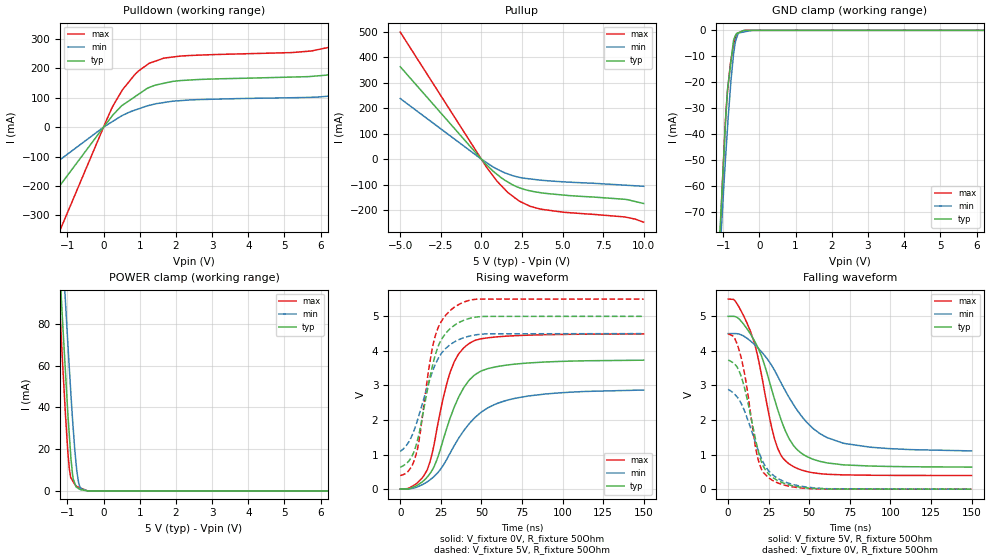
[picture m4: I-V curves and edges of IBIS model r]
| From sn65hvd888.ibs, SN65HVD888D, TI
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|   r Model
[Model]   r
Model_type   3-state
Polarity   Non-Inverting
Vmeas = 2.5
Vref = 2.5
Cref = 2pF
Rref = 50
|   typ   min   max
|   (nom PVT)   (fast PVT)   (slow PVT)
|C_comp from frequency sweep method (F=125KHz)
|C_comp   1.495e-10   1.150e-10   1.824e-10
|ON state : BUFFER OUTPUT TURNED HIGH
|C_comp   1.495e-10   1.150e-10   1.824e-10
|OFF state: BUFFER IN HIGH IMPEDANCE
|C_comp   4.798e-12   4.384e-12   5.241e-12
|C_comp from LC tank measurement(L=1nH)
|Resonant Frequency(Hz)   2.830e+09   3.020e+09   2.690e+09
 C_comp   3.166e-12   2.780e-12   3.504e-12
|ON state : BUFFER OUTPUT TURNED HIGH
|Resonant Frequency(Hz)   2.830e+09   3.020e+09   2.690e+09
|C_comp   3.166e-12   2.780e-12   3.504e-12
|OFF state: BUFFER IN HIGH IMPEDANCE
|Resonant Frequency(Hz)   2.980e+09   3.140e+09   2.880e+09
|C_comp   2.855e-12   2.572e-12   3.057e-12
| Where nom  PVT is Nominal Process, 5V, 27C
|   Fast PVT is Strong Process,  5.5V, -40C
|   Slow PVT is Weak Process,   4.5V, 125C
[Voltage Range]   5   4.5   5.5
|Ambient Temperature   25   85   -40
|Junction Temperature
[Temperature Range]   27   125   -40
[Pullup Reference]   5   4.5   5.5
[Pulldown Reference]   0   0   0
[Power Clamp Reference]   5   4.5   5.5
[GND Clamp Reference]   0   0   0
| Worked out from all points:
|   slope of the pulldown table from 0 to 0.75 V, typ, clamps not added: 8.01 ohm
|   slope of the pullup table from 0 to 0.75 V, typ, clamps not added: 15.5 ohm
|   GND clamp passes 1 mA (typ) near -0.59 V on its own axis
|   POWER clamp passes 1 mA (typ) near -0.68 V on its own axis
|   falling waveform, V_fixture 5V, R_fixture 50Ohm: 20-80 % time 19ns typ, 28.4ns min, 14.5ns max; typ from 5 V to 0.638 V
|   rising waveform, V_fixture 0V, R_fixture 50Ohm: 20-80 % time 18.2ns typ, 27.3ns min, 13.6ns max; typ from 0 V to 3.73 V
|   rising waveform, V_fixture 5V, R_fixture 50Ohm: 20-80 % time 12.2ns typ, 14.8ns min, 10.3ns max; typ from 0.635 V to 5 V
|   falling waveform, V_fixture 0V, R_fixture 50Ohm: 20-80 % time 11.1ns typ, 14.5ns min, 9.3ns max; typ from 3.74 V to 0 V
[Pulldown]
|   Voltage   I(typ)   I(min)   I(max)
-5V       -822.3mA   -460.4mA   -1.456A
-4.5mV    -740.1uA   -414.4uA   -1.31mA
522.5mV   74.52mA    39.88mA    127.1mA
874.5mV   104mA      58.16mA    180.1mA
1.265V    135mA      74.09mA    217.1mA
2.118V    158.1mA    90mA       241.4mA
5.737V    172.3mA    101.3mA    258.6mA
6.885V    195.8mA    112.5mA    302.7mA
7.81V     256.8mA    149.4mA    409mA
8.602V    370.2mA    204.2mA    600.7mA
9.664V    672.7mA    329.7mA    1.08A
10V       798.2mA    369.6mA    1.3A
[GND Clamp]
|   Voltage   I(typ)   I(min)   I(max)
-5V       -1.663A    -1.421A    -1.927A
-1.085V   -75.85mA   -84.47mA   -79.21mA
-1.023V   -58.9mA    -69.61mA   -58.82mA
-935mV    -34.66mA   -48.94mA   -34.05mA
-880mV    -22.6mA    -37.16mA   -23.23mA
-803mV    -13.86mA   -22.52mA   -13.14mA
-783mV    -11.59mA   -18.85mA   -11.3mA
-715mV    -3.873mA   -9.28mA    -5.401mA
-652.5mV  -1.723mA   -3.775mA   -2.647mA
-580.5mV  -943.3uA   -1.033mA   -964.3uA
-435mV    -25.86uA   -635.9uA   -185.2uA
10V       0A         0A         0A
[Pullup]
|   Voltage   I(typ)   I(min)   I(max)
-5V       363.7mA    238.5mA    499.8mA
335.5mV   -23.11mA   -14.22mA   -33.28mA
968mV     -59.94mA   -38.98mA   -86.91mA
1.672V    -91.39mA   -58.89mA   -133.2mA
2.376V    -113.3mA   -72mA      -166.2mA
2.959V    -124mA     -77.39mA   -184mA
3.547V    -130.8mA   -81.81mA   -194.7mA
5.027V    -140.9mA   -88.99mA   -208.3mA
8.85V     -157.9mA   -102.2mA   -227.2mA
9.471V    -166.3mA   -104.6mA   -235.6mA
10V       -174.4mA   -106.7mA   -247.8mA
[POWER Clamp]
|   Voltage   I(typ)   I(min)   I(max)
-5V       1.49A      1.478A     1.515A
-1.373V   160.4mA    192.8mA    143mA
-1.14V    83.35mA    118.2mA    63.82mA
-1.062V   59.6mA     93.17mA    39.33mA
-990mV    37.68mA    71.37mA    19.36mA
-946mV    26.56mA    58.56mA    10.54mA
-900mV    15.16mA    45.59mA    6.169mA
-855mV    7.547mA    33.68mA    4.864mA
-738mV    1.705mA    9.296mA    2.12mA
-688.5mV  1.1mA      3.894mA    1.763mA
-630mV    566.9uA    1.246mA    1.341mA
10V       0A         0A         0A
[Ramp]
R_load = 50
|   typ   min   max
dV/dt_r   2.23907/1.80688e-08   1.7209/2.71764e-08   2.69435/1.34681e-08
dV/dt_f   2.61695/1.90148e-08   2.03585/2.84067e-08   3.06325/1.44155e-08
[Falling Waveform]
V_fixture = 5V
V_fixture_min = 4.5V
V_fixture_max = 5.5V
R_fixture = 50Ohm
|   Time   V(typ)   V(min)   V(max)
0s        5V         4.5V       5.5V
4.56ns    4.989V     4.5V       5.429V
13.86ns   4.482V     4.283V     4.551V
20.55ns   3.85V      3.973V     3.306V
28.74ns   2.576V     3.424V     1.429V
32.52ns   2.019V     3.085V     984.1mV
37.14ns   1.499V     2.687V     745.1mV
52.47ns   862.7mV    1.751V     473.6mV
70.39ns   706.5mV    1.337V     414.4mV
150ns     638.4mV    1.107V     394.6mV
[Rising Waveform]
V_fixture = 0V
V_fixture_min = 0V
V_fixture_max = 0V
R_fixture = 50Ohm
|   Time   V(typ)   V(min)   V(max)
0s        905.4pV    46.66nV    283.7pV
9.35ns    83.25mV    44.73mV    137.6mV
16.65ns   350.7mV    212.8mV    563.1mV
22.55ns   845.1mV    448.3mV    1.729V
30.73ns   2.056V     1.043V     3.38V
35.93ns   2.658V     1.469V     3.908V
42.7ns    3.165V     1.905V     4.224V
54.29ns   3.491V     2.361V     4.381V
71.75ns   3.623V     2.638V     4.443V
150ns     3.732V     2.868V     4.491V
[Rising Waveform]
V_fixture = 5V
V_fixture_min = 4.5V
V_fixture_max = 5.5V
R_fixture = 50Ohm
|   Time   V(typ)   V(min)   V(max)
0s        635.2mV    1.09V      394mV
6.21ns    875.2mV    1.446V     599.6mV
10.5ns    1.391V     1.977V     1.137V
12.37ns   1.772V     2.274V     1.65V
18.11ns   3.192V     3.16V      3.626V
21.9ns    3.928V     3.64V      4.484V
25.3ns    4.326V     3.926V     4.853V
33.14ns   4.734V     4.254V     5.257V
51.2ns    4.996V     4.488V     5.5V
150ns     5V         4.5V       5.5V
[Falling Waveform]
V_fixture = 0V
V_fixture_min = 0V
V_fixture_max = 0V
R_fixture = 50Ohm
|   Time   V(typ)   V(min)   V(max)
0s        3.739V     2.891V     4.493V
4.09ns    3.615V     2.74V      4.357V
8.12ns    3.25V      2.472V     3.784V
11.38ns   2.675V     2.098V     2.991V
16.66ns   1.487V     1.376V     1.258V
18.98ns   1.03V      1.071V     775.8mV
22.5ns    591.3mV    698.9mV    442.1mV
26.93ns   357.5mV    436.4mV    264.6mV
56.57ns   11.43mV    25mV       3.969mV
150ns     2.628uV    7.767uV    820.3nV
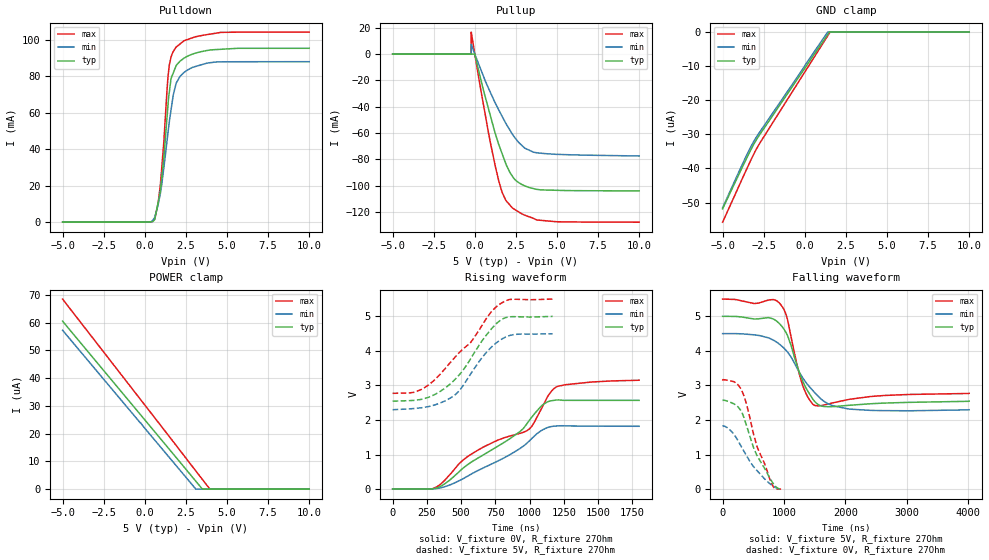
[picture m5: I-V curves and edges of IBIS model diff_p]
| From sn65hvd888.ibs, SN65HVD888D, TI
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|   diff Model
[Model]   diff_p
Model_type   I/O
Polarity   Non-Inverting
Enable   Active-High
Vinl = 0.8
Vinh = 2
Vmeas = 2.5
Vref = 2.5
Cref = 50pF
Rref = 27
|   typ   min   max
|   (nom PVT)   (fast PVT)   (slow PVT)
|C_comp from frequency sweep method (F=125KHz)
|Average
|C_comp   9.846e-10   2.587e-10   1.376e-09
|ON state : BUFFER OUTPUT TURNED HIGH
|C_comp   1.960e-09   5.074e-10   2.742e-09
|OFF state: BUFFER IN HIGH IMPEDANCE
C_comp   9.656e-12   9.606e-12   9.919e-12
|C_comp from LC tank measurement(L=1nH )
|Average
|Resonant Frequency(Hz)   2.210e+09   2.275e+09   2.12e+09
| C_comp   5.230e-12   4.977e-12   5.687e-12
|ON state : BUFFER OUTPUT TURNED HIGH
|Resonant Frequency(Hz)   2.100e+09   2.110e+09   2.010e+09
| C_comp   5.750e-12   5.695e-12   6.276e-12
|OFF state: BUFFER IN HIGH IMPEDANCE
|Resonant Frequency(Hz)   2.320e+09   2.440e+09   2.230e+09
|C_comp   4.711e-12   4.259e-12   5.099e-12
| Where nom  PVT is Nominal Process, 5V, 27C
|   Fast PVT is Strong Process,  5.5V, -40C
|   Slow PVT is Weak Process,   4.5V, 125C
[Voltage Range]   5   4.5   5.5
|Ambient Temperature   25   85   -40
|Junction Temperature
[Temperature Range]   27   125   -40
[Pullup Reference]   5   4.5   5.5
[Pulldown Reference]   0   0   0
[Power Clamp Reference]   5   4.5   5.5
[GND Clamp Reference]   0   0   0
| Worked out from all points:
|   slope of the pulldown table from 0 to 0.75 V, typ, clamps not added: 92.7 ohm
|   slope of the pullup table from 0 to 0.75 V, typ, clamps not added: 19.9 ohm
|   falling waveform, V_fixture 5V, R_fixture 27Ohm: 20-80 % time 289ns typ, 519ns min, 201ns max; typ from 5 V to 2.55 V
|   rising waveform, V_fixture 0V, R_fixture 27Ohm: 20-80 % time 522ns typ, 471ns min, 648ns max; typ from 0 V to 2.57 V
|   rising waveform, V_fixture 5V, R_fixture 27Ohm: 20-80 % time 276ns typ, 249ns min, 342ns max; typ from 2.55 V to 5 V
|   falling waveform, V_fixture 0V, R_fixture 27Ohm: 20-80 % time 360ns typ, 415ns min, 328ns max; typ from 2.57 V to 0 V
[Pulldown]
|   Voltage   I(typ)   I(min)   I(max)
-5V       0A         0A         0A
599.5mV   1.483mA    2.701mA    1.704mA
808.5mV   10.72mA    9.647mA    10.26mA
940.5mV   16.87mA    15.44mA    20.12mA
1.155V    34.87mA    29.62mA    43.62mA
1.342V    56.38mA    43.81mA    71.14mA
1.49V     71.3mA     55.01mA    86.23mA
1.595V    78.84mA    61.54mA    90.63mA
1.908V    85.97mA    76.32mA    96.15mA
2.376V    89.99mA    82.14mA    99.54mA
4.253V    94.72mA    87.87mA    103.6mA
10V       95.48mA    88.11mA    104.4mA
[GND Clamp]
|   Voltage   I(typ)   I(min)   I(max)
-5V       -51.86uA   -51.56uA   -55.78uA
-3.618V   -37.81uA   -36.94uA   -41.05uA
-3.348V   -35.16uA   -34.26uA   -38.25uA
-2.979V   -31.87uA   -31.07uA   -34.6uA
1.391V    -727.2nA   -11.06nA   -1.113uA
1.49V     -20.19nA   0A         -354.6nA
1.534V    -18.05nA   0A         -15.41nA
10V       0A         0A         0A
[Pullup]
|   Voltage   I(typ)   I(min)   I(max)
-5V       0A         0A         0A
-220.5mV  0A         0A         0A
-216mV    8.022nA    7.47mA     16.79mA
0V        0A         0A         0A
830.5mV   -41.37mA   -25.83mA   -59.55mA
1.27V     -61.27mA   -37.72mA   -86.48mA
1.672V    -75.95mA   -47.52mA   -105.3mA
2.272V    -92.48mA   -60.52mA   -116.6mA
3.038V    -100.1mA   -71.38mA   -122.4mA
3.568V    -102.2mA   -74.52mA   -124.8mA
4.944V    -103.5mA   -76.15mA   -127.4mA
10V       -103.9mA   -77.39mA   -127.7mA
[POWER Clamp]
|   Voltage   I(typ)   I(min)   I(max)
-5V       60.53uA    57.22uA    68.48uA
3.105V    2.86uA     20.72nA    6.55uA
3.505V    15.34nA    0A         3.496uA
3.96V     0A         0A         26.51nA
10V       0A         0A         0A
[Ramp]
R_load = 27
|   typ   min   max
dV/dt_r   1.54172/5.22245e-07   1.08966/4.7065e-07   1.89926/6.48578e-07
dV/dt_f   1.47458/2.87919e-07   1.32296/5.19379e-07   1.63872/2.01531e-07
[Falling Waveform]
V_fixture = 5V
V_fixture_min = 4.5V
V_fixture_max = 5.5V
R_fixture = 27Ohm
|   Time   V(typ)   V(min)   V(max)
0s        5V         4.5V       5.5V
608.6ns   4.934V     4.441V     5.397V
821.1ns   4.928V     4.317V     5.485V
938.3ns   4.765V     4.176V     5.358V
1.05us    4.467V     3.981V     4.95V
1.3us     3.142V     3.232V     3.018V
1.503us   2.529V     2.785V     2.421V
1.713us   2.386V     2.474V     2.462V
2.074us   2.428V     2.316V     2.603V
4.013us   2.546V     2.298V     2.772V
[Rising Waveform]
V_fixture = 0V
V_fixture_min = 0V
V_fixture_max = 0V
R_fixture = 27Ohm
|   Time   V(typ)   V(min)   V(max)
0s        285.9uV    266.1uV    315.9uV
323.8ns   36.16mV    20.04mV    71.21mV
586.7ns   815.1mV    465.2mV    1.043V
926.5ns   1.657V     1.169V     1.611V
996.8ns   1.986V     1.393V     1.738V
1.091us   2.427V     1.709V     2.366V
1.141us   2.541V     1.796V     2.739V
1.196us   2.579V     1.828V     2.96V
1.269us   2.571V     1.829V     3.026V
1.799us   2.57V      1.819V     3.152V
[Rising Waveform]
V_fixture = 5V
V_fixture_min = 4.5V
V_fixture_max = 5.5V
R_fixture = 27Ohm
|   Time   V(typ)   V(min)   V(max)
0s        2.546V     2.298V     2.772V
155.9ns   2.569V     2.333V     2.801V
214.9ns   2.601V     2.357V     2.893V
389ns     2.943V     2.566V     3.516V
480.8ns   3.282V     2.825V     3.93V
569.4ns   3.773V     3.334V     4.246V
673.2ns   4.403V     3.906V     4.871V
789.5ns   4.894V     4.324V     5.373V
888.7ns   4.99V      4.475V     5.494V
1.168us   4.998V     4.496V     5.499V
[Falling Waveform]
V_fixture = 0V
V_fixture_min = 0V
V_fixture_max = 0V
R_fixture = 27Ohm
|   Time   V(typ)   V(min)   V(max)
0s        2.57V      1.816V     3.166V
128ns     2.513V     1.7V       3.135V
288.7ns   2.295V     1.281V     2.929V
392ns     1.827V     959.4mV    2.439V
521.9ns   1.123V     613.6mV    1.474V
560.8ns   972.1mV    536mV      1.228V
691.4ns   577mV      283.5mV    701.7mV
791.6ns   251.1mV    126.2mV    188.4mV
861.5ns   80.11mV    48.63mV    10.42mV
951.7ns   453.4uV    850.7uV    570.3uV
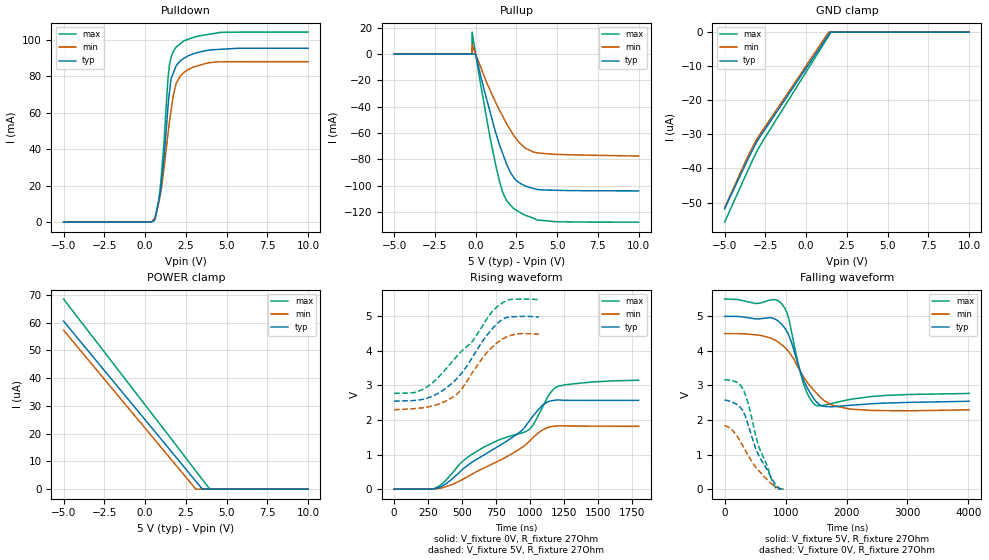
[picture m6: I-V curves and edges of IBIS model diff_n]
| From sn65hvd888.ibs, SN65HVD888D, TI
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[Model]   diff_n
Model_type   I/O
Polarity   Non-Inverting
Enable   Active-High
Vinl = 0.8
Vinh = 2
Vmeas = 2.5
Vref = 2.5
Cref = 50pF
Rref = 27
|   typ   min   max
|   (nom PVT)   (fast PVT)   (slow PVT)
|C_comp from frequency sweep method (F=125KHz)
|Average
| C_comp   4.287e-09   3.218e-09   4.932e-09
|ON state : BUFFER OUTPUT TURNED HIGH
| C_comp   8.564e-09   6.426e-09   9.855e-09
|OFF state: BUFFER IN HIGH IMPEDANCE
C_comp   9.656e-12  9.606e-12   9.919e-12
|C_comp from LC tank measurement(L=1nH )
|Average
|Resonant Frequency(Hz)   1.865e+09   1.975e+09   1.77e+09
| C_comp   8.7305e-12   7.6895e-12   9.9395e-12
|ON state : BUFFER OUTPUT TURNED HIGH
|Resonant Frequency(Hz)   1.410e+09   1.510e+09   1.310e+09
| C_comp   1.275e-11   1.112e-11   1.478e-11
|OFF state: BUFFER IN HIGH IMPEDANCE
|Resonant Frequency(Hz)   2.320e+09   2.440e+09   2.230e+09
|C_comp   4.711e-12   4.259e-12   5.099e-12
| Where nom  PVT is Nominal Process, 5V, 27C
|   Fast PVT is Strong Process,  5.5V, -40C
|   Slow PVT is Weak Process,   4.5V, 125C
[Voltage Range]   5   4.5   5.5
|Ambient Temperature   25   85   -40
|Junction Temperature
[Temperature Range]   27   125   -40
[Pullup Reference]   5   4.5   5.5
[Pulldown Reference]   0   0   0
[Power Clamp Reference]   5   4.5   5.5
[GND Clamp Reference]   0   0   0
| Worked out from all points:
|   slope of the pulldown table from 0 to 0.75 V, typ, clamps not added: 92.7 ohm
|   slope of the pullup table from 0 to 0.75 V, typ, clamps not added: 19.9 ohm
|   falling waveform, V_fixture 5V, R_fixture 27Ohm: 20-80 % time 289ns typ, 519ns min, 201ns max; typ from 5 V to 2.55 V
|   rising waveform, V_fixture 0V, R_fixture 27Ohm: 20-80 % time 522ns typ, 471ns min, 648ns max; typ from 0 V to 2.57 V
|   rising waveform, V_fixture 5V, R_fixture 27Ohm: 20-80 % time 274ns typ, 247ns min, 340ns max; typ from 2.55 V to 4.98 V
|   falling waveform, V_fixture 0V, R_fixture 27Ohm: 20-80 % time 360ns typ, 415ns min, 328ns max; typ from 2.57 V to 0 V
[Pulldown]
|   Voltage   I(typ)   I(min)   I(max)
-5V       0A         0A         0A
599.5mV   1.483mA    2.701mA    1.704mA
808.5mV   10.72mA    9.647mA    10.26mA
940.5mV   16.87mA    15.44mA    20.12mA
1.155V    34.87mA    29.62mA    43.62mA
1.342V    56.38mA    43.81mA    71.14mA
1.49V     71.3mA     55.01mA    86.23mA
1.595V    78.84mA    61.54mA    90.63mA
1.908V    85.97mA    76.32mA    96.15mA
2.376V    89.99mA    82.14mA    99.54mA
4.253V    94.72mA    87.87mA    103.6mA
10V       95.48mA    88.11mA    104.4mA
[GND Clamp]
|   Voltage   I(typ)   I(min)   I(max)
-5V       -51.83uA   -51.53uA   -55.75uA
-3.623V   -37.83uA   -36.96uA   -41.07uA
-3.127V   -33.1uA    -32.24uA   -36uA
-2.75V    -30.12uA   -29.37uA   -32.66uA
1.386V    -732.6nA   -18.89nA   -1.118uA
1.485V    -29.22nA   0A         -363nA
1.529V    0A         0A         -27.59nA
10V       0A         0A         0A
[Pullup]
|   Voltage   I(typ)   I(min)   I(max)
-5V       0A         0A         0A
-220.5mV  0A         0A         0A
-216mV    8.022nA    7.47mA     16.79mA
0V        0A         0A         0A
830.5mV   -41.37mA   -25.83mA   -59.55mA
1.27V     -61.27mA   -37.72mA   -86.48mA
1.672V    -75.95mA   -47.52mA   -105.3mA
2.272V    -92.48mA   -60.52mA   -116.6mA
3.038V    -100.1mA   -71.38mA   -122.4mA
3.568V    -102.2mA   -74.52mA   -124.8mA
4.944V    -103.5mA   -76.15mA   -127.4mA
10V       -103.9mA   -77.39mA   -127.7mA
[POWER Clamp]
|   Voltage   I(typ)   I(min)   I(max)
-5V       60.56uA    57.25uA    68.51uA
3.11V     2.854uA    12.87nA    6.544uA
3.51V     6.303nA    0A         3.487uA
3.966V    0A         0A         14.34nA
10V       0A         0A         0A
[Ramp]
R_load = 27
|   typ   min   max
dV/dt_r   1.54172/5.22299e-07   1.08966/4.70692e-07   1.89926/6.48618e-07
dV/dt_f   1.47458/2.87921e-07   1.32296/5.19378e-07   1.63872/2.01538e-07
[Falling Waveform]
V_fixture = 5V
V_fixture_min = 4.5V
V_fixture_max = 5.5V
R_fixture = 27Ohm
C_fixture = 0F
|   Time   V(typ)   V(min)   V(max)
0s        5V         4.5V       5.5V
608.7ns   4.934V     4.441V     5.397V
821ns     4.928V     4.317V     5.485V
938.4ns   4.764V     4.176V     5.358V
1.05us    4.467V     3.981V     4.95V
1.3us     3.142V     3.232V     3.019V
1.503us   2.529V     2.785V     2.421V
1.713us   2.386V     2.474V     2.462V
2.074us   2.428V     2.316V     2.603V
4.012us   2.546V     2.298V     2.772V
[Rising Waveform]
V_fixture = 0V
V_fixture_min = 0V
V_fixture_max = 0V
R_fixture = 27Ohm
C_fixture = 0F
|   Time   V(typ)   V(min)   V(max)
0s        285.2uV    265.5uV    315.1uV
323.8ns   36.19mV    20.06mV    71.28mV
586.7ns   815.2mV    465.3mV    1.044V
926.5ns   1.657V     1.169V     1.611V
996.8ns   1.986V     1.393V     1.738V
1.091us   2.427V     1.709V     2.366V
1.141us   2.541V     1.796V     2.739V
1.196us   2.579V     1.827V     2.96V
1.269us   2.571V     1.829V     3.026V
1.799us   2.57V      1.819V     3.152V
[Rising Waveform]
V_fixture = 5V
V_fixture_min = 4.5V
V_fixture_max = 5.5V
R_fixture = 27Ohm
C_fixture = 0F
|   Time   V(typ)   V(min)   V(max)
0s        2.546V     2.298V     2.772V
155.9ns   2.569V     2.333V     2.801V
214.9ns   2.601V     2.357V     2.893V
389.1ns   2.943V     2.566V     3.516V
480.8ns   3.282V     2.825V     3.93V
569.4ns   3.773V     3.334V     4.246V
673.2ns   4.403V     3.906V     4.871V
789.3ns   4.893V     4.324V     5.372V
930.1ns   5V         4.5V       5.5V
1.066us   4.979V     4.484V     5.481V
[Falling Waveform]
V_fixture = 0V
V_fixture_min = 0V
V_fixture_max = 0V
R_fixture = 27Ohm
C_fixture = 0F
|   Time   V(typ)   V(min)   V(max)
0s        2.57V      1.816V     3.166V
128ns     2.513V     1.7V       3.135V
288.7ns   2.295V     1.281V     2.929V
392ns     1.827V     959.3mV    2.439V
521.9ns   1.123V     613.6mV    1.474V
560.8ns   972.1mV    536mV      1.228V
691.4ns   577mV      283.5mV    701.8mV
791.6ns   251.1mV    126.2mV    188.5mV
861.5ns   80.11mV    48.62mV    10.43mV
971.7ns   452.8uV    849.9uV    569.6uV
